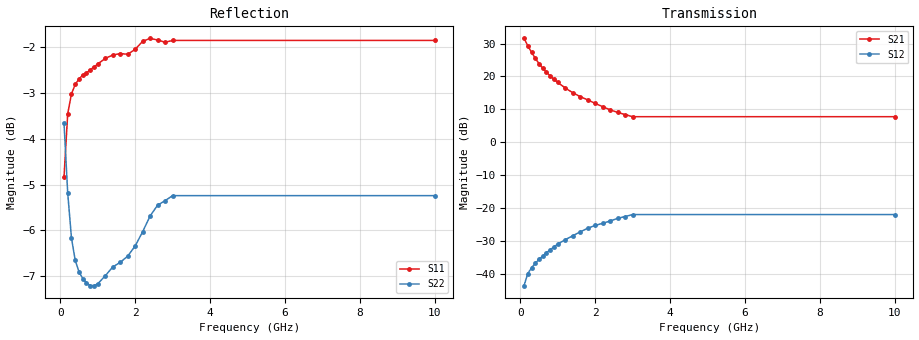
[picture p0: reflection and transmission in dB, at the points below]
! Filename: 2100BFG480.001
! Title: BFG480W
! Bias: Vce=2V; Ic=100mA
! Company: Philips Semiconductors NL
! User: Quality&Reliability T&D
! Measure time: 10 Nov 1999 / 11:55:01
#  MHz  S  MA  R 50
! Freq  S11  S21  S12  S22  :
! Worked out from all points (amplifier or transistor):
!   21 points, 100 MHz to 10 GHz, reference 50 ohm
!   highest |S21| = 31.6 dB at 100 MHz (marker M1)
!   |S21| within 3 dB of that: start of sweep to 239.5 MHz
!   unconditionally stable (mu >= 1): 582.6 MHz to end of sweep
!   at 400 MHz: K = 0.89, MSG = 31.1 dB, |S12| = -36.8 dB
!   at 1.2 GHz: K = 1.11, MAG = 21.0 dB, |S12| = -29.6 dB
!   at 10 GHz: K = 1.11, MAG = 12.9 dB, |S12| = -21.9 dB
!   S11 on the Smith chart (normalised r, x): 100 MHz: 0.28, -0.15; 300 MHz: 0.17, -0.08; 1.4 GHz: 0.13, +0.10; 2.2 GHz: 0.11, +0.18; 10 GHz: 0.11, +0.26
100  0.5728 -161.8  37.95 141.9  0.006639 66.7  0.657 -52.1
200  0.6723 -166.8  29.38 121.8  0.01014 58.7  0.5502 -88.5
300  0.7065 -171.1  23.43 110.7  0.01242 58.6  0.4914 -110.5
400  0.7239 -174.4  18.88 103.2  0.01452 60.4  0.4645 -124.6
500  0.7333 -177.1  15.72 97.8  0.01663 62.9  0.4515 -134.3
600  0.7411 -179.3  13.32 93.6  0.01876 64.8  0.4437 -141.2
700  0.7449 178.7  11.55 90.2  0.02106 66.8  0.4387 -146.5
800  0.7508 176.9  10.14 87.2  0.02337 68.2  0.436 -150.8
900  0.7561 175.2  9.017 84.8  0.02571 70.1  0.4358 -154.4
1000  0.7618 173.6  8.119 82.4  0.0284 70.8  0.4378 -157.7
1200  0.7725 170.7  6.701 77.8  0.03317 72.2  0.4467 -162.8
1400  0.7792 168.5  5.666 73.3  0.03804 72.8  0.4567 -166.6
1600  0.7822 166.1  4.948 69.6  0.04358 73.3  0.4622 -169.7
1800  0.7808 163.6  4.411 66.3  0.04951 73.7  0.4694 -173.0
2000  0.7905 161.4  3.904 63.6  0.05463 74.0  0.4816 -176.6
2200  0.8066 159.4  3.479 60.2  0.05891 73.9  0.4992 -179.7
2400  0.8127 157.6  3.115 56.7  0.06382 73.3  0.5195 178.4
2600  0.8094 155.8  2.849 53.5  0.06997 72.4  0.5338 177.2
2800  0.8047 153.5  2.639 49.1  0.07457 71.0  0.5399 175.3
3000  0.8085 150.8  2.451 45.8  0.07994 70.1  0.5468 172.6
10000  0.8085 150.8  2.451 45.8  0.07993 70.1  0.5468 172.6
